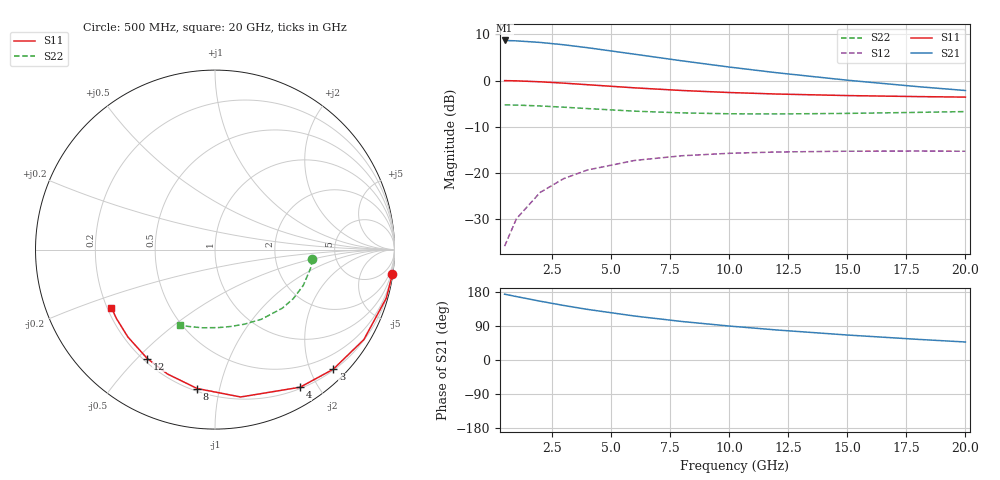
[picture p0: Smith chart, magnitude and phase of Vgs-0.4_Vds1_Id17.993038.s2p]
# Hz S RI R 50
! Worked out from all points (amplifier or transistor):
!   12 points, 500 MHz to 20 GHz, reference 50 ohm
!   highest |S21| = 8.7 dB at 500 MHz (marker M1)
!   |S21| within 3 dB of that: start of sweep to 6.039 GHz
!   unconditionally stable (mu >= 1): 13.18 GHz to end of sweep
!   at 2 GHz: K = 0.15, MSG = 16.2 dB, |S12| = -24.2 dB
!   at 8 GHz: K = 0.61, MSG = 10.3 dB, |S12| = -16.3 dB
!   at 20 GHz: K = 1.54, MAG = 2.2 dB, |S12| = -15.3 dB
!   S11 on the Smith chart (normalised r, x): 500 MHz: 0, -14; 3 GHz: 0.22, -2.38; 4 GHz: 0.22, -1.77; 8 GHz: 0.22, -0.86; 12 GHz: 0.22, -0.54; 20 GHz: 0.22, -0.25
5e8  0.9882 -0.1385  -2.696 0.2999  0.00153 0.0161  0.5429 -0.0537
1e9  0.9539 -0.2712  -2.62 0.5871  0.00599 0.0314  0.532 -0.1056
2e9  0.8294 -0.5012  -2.346 1.082  0.0221 0.0574  0.4922 -0.1988
3e9  0.6585 -0.6667  -1.969 1.434  0.0442 0.0748  0.4368 -0.2724
4e9  0.4738 -0.7668  -1.564 1.641  0.0678 0.0836  0.3754 -0.3262
6e9  0.1429 -0.8211  -0.8451 1.732  0.1092 0.0822  0.2591 -0.3879
8e9  -0.0994 -0.774  -0.3297 1.6  0.1378 0.0677  0.1629 -0.4158
1e10  -0.2647 -0.6931  0.00878 1.4  0.1555 0.0496  0.0846 -0.4287
1.2e10  -0.3772 -0.6071  0.2257 1.195  0.1656 0.0317  0.018 -0.4346
1.5e10  -0.4848 -0.4876  0.4109 0.9207  0.1719 0.00758  -0.0689 -0.4356
1.8e10  -0.5492 -0.3841  0.4991 0.698  0.1721 -0.0124  -0.1458 -0.4284
2e10  -0.5775 -0.3231  0.5269 0.5752  0.1703 -0.0238  -0.193 -0.4192
